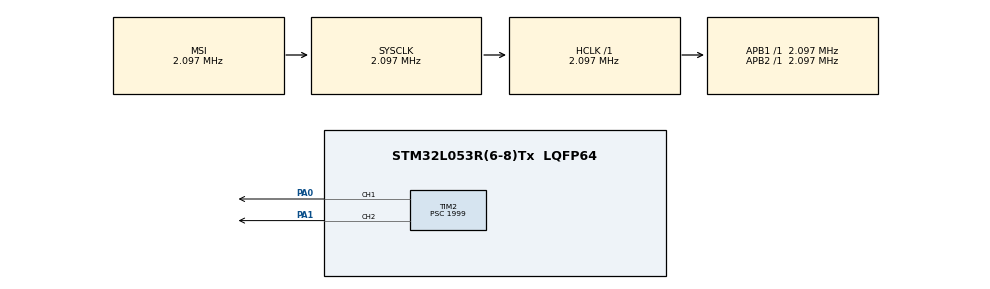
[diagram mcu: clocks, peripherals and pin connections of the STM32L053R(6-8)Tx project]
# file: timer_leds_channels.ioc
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Dma.Request0=TIM2_UP
Dma.TIM2_UP.0.Direction=DMA_PERIPH_TO_MEMORY
Dma.TIM2_UP.0.Instance=DMA1_Channel2
Dma.TIM2_UP.0.MemDataAlignment=DMA_MDATAALIGN_HALFWORD
Dma.TIM2_UP.0.MemInc=DMA_MINC_ENABLE
Dma.TIM2_UP.0.Mode=DMA_CIRCULAR
Dma.TIM2_UP.0.PeriphDataAlignment=DMA_PDATAALIGN_HALFWORD
Dma.TIM2_UP.0.PeriphInc=DMA_PINC_DISABLE
Dma.TIM2_UP.0.Priority=DMA_PRIORITY_LOW
Mcu.Family=STM32L0
Mcu.Name=STM32L053R(6-8)Tx
Mcu.Package=LQFP64
NVIC.DMA1_Channel2_3_IRQn=true\:0\:0\:false\:false\:true\:false\:true\:true
NVIC.TIM2_IRQn=true\:0\:0\:false\:false\:true\:true\:true\:true
PA0.Signal=S_TIM2_CH1
PA1.Signal=S_TIM2_CH2
ProjectManager.HeapSize=0x200
ProjectManager.StackSize=0x400
ProjectManager.TargetToolchain=STM32CubeIDE
RCC.AHBFreq_Value=2097000
RCC.APB1Freq_Value=2097000
RCC.APB1TimFreq_Value=2097000
RCC.APB2Freq_Value=2097000
RCC.APB2TimFreq_Value=2097000
RCC.HSE_VALUE=8000000
RCC.HSI16_VALUE=16000000
RCC.HSI48_VALUE=48000000
RCC.HSI_VALUE=16000000
RCC.LSE_VALUE=32768
RCC.MSI_VALUE=2097000
RCC.SYSCLKFreq_VALUE=2097000
RCC.VCOOutputFreq_Value=48000000
SH.S_TIM2_CH1.0=TIM2_CH1,Output Compare1 CH1
SH.S_TIM2_CH2.0=TIM2_CH2,Output Compare2 CH2
TIM2.Channel-Output\ Compare1\ CH1=TIM_CHANNEL_1
TIM2.Channel-Output\ Compare2\ CH2=TIM_CHANNEL_2
TIM2.OCMode_1=TIM_OCMODE_TOGGLE
TIM2.OCMode_2=TIM_OCMODE_TOGGLE
TIM2.Period=999
TIM2.Prescaler=1999
VP_TIM2_VS_ClockSourceINT.Mode=Internal
board=custom

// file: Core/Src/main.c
/* USER CODE BEGIN Header */
/**
  ******************************************************************************
  * @file           : main.c
  * @brief          : Main program body
  ******************************************************************************
  * @attention
  *
  * Copyright (c) 2023 STMicroelectronics.
  * All rights reserved.
  *
  * This software is licensed under terms that can be found in the LICENSE file
  * in the root directory of this software component.
  * If no LICENSE file comes with this software, it is provided AS-IS.
  *
  ******************************************************************************
  */
/* USER CODE END Header */
#include "main.h"

TIM_HandleTypeDef htim2;
DMA_HandleTypeDef hdma_tim2_up;

void SystemClock_Config(void);
static void MX_GPIO_Init(void);
static void MX_DMA_Init(void);
static void MX_TIM2_Init(void);

int main(void)
{

  /* MCU Configuration--------------------------------------------------------*/

  /* Reset of all peripherals, Initializes the Flash interface and the Systick. */
  HAL_Init();

  /* Configure the system clock */
  SystemClock_Config();

  /* Initialize all configured peripherals */
  MX_GPIO_Init();
  MX_DMA_Init();
  MX_TIM2_Init();
  /* USER CODE BEGIN 2 */
//  uint8_t data[] = {0xFF, 0x0};
//  HAL_TIM_Base_Start(&htim2);
//  HAL_DMA_Start(&hdma_tim2_up, (uint32_t)data, (uint32_t)&GPIOA->ODR, 2);
//  __HAL_TIM_ENABLE_DMA(&htim2, TIM_DMA_UPDATE);
  HAL_TIM_OC_Start(&htim2, TIM_CHANNEL_1);
  HAL_TIM_OC_Start(&htim2, TIM_CHANNEL_2);
  /* USER CODE END 2 */

  /* Infinite loop */
  while (1)
  {

  }
}

void SystemClock_Config(void)
{
  RCC_OscInitTypeDef RCC_OscInitStruct = {0};
  RCC_ClkInitTypeDef RCC_ClkInitStruct = {0};

  /** Configure the main internal regulator output voltage
  */
  __HAL_PWR_VOLTAGESCALING_CONFIG(PWR_REGULATOR_VOLTAGE_SCALE1);

  /** Initializes the RCC Oscillators according to the specified parameters
  * in the RCC_OscInitTypeDef structure.
  */
  RCC_OscInitStruct.OscillatorType = RCC_OSCILLATORTYPE_MSI;
  RCC_OscInitStruct.MSIState = RCC_MSI_ON;
  RCC_OscInitStruct.MSICalibrationValue = 0;
  RCC_OscInitStruct.MSIClockRange = RCC_MSIRANGE_5;
  RCC_OscInitStruct.PLL.PLLState = RCC_PLL_NONE;
  if (HAL_RCC_OscConfig(&RCC_OscInitStruct) != HAL_OK)
  {
    Error_Handler();
  }

  /** Initializes the CPU, AHB and APB buses clocks
  */
  RCC_ClkInitStruct.ClockType = RCC_CLOCKTYPE_HCLK|RCC_CLOCKTYPE_SYSCLK
                              |RCC_CLOCKTYPE_PCLK1|RCC_CLOCKTYPE_PCLK2;
  RCC_ClkInitStruct.SYSCLKSource = RCC_SYSCLKSOURCE_MSI;
  RCC_ClkInitStruct.AHBCLKDivider = RCC_SYSCLK_DIV1;
  RCC_ClkInitStruct.APB1CLKDivider = RCC_HCLK_DIV1;
  RCC_ClkInitStruct.APB2CLKDivider = RCC_HCLK_DIV1;

  if (HAL_RCC_ClockConfig(&RCC_ClkInitStruct, FLASH_LATENCY_0) != HAL_OK)
  {
    Error_Handler();
  }
}

static void MX_TIM2_Init(void)
{

  TIM_ClockConfigTypeDef sClockSourceConfig = {0};
  TIM_MasterConfigTypeDef sMasterConfig = {0};
  TIM_OC_InitTypeDef sConfigOC = {0};

  htim2.Instance = TIM2;
  htim2.Init.Prescaler = 1999;
  htim2.Init.CounterMode = TIM_COUNTERMODE_UP;
  htim2.Init.Period = 999;
  htim2.Init.ClockDivision = TIM_CLOCKDIVISION_DIV1;
  htim2.Init.AutoReloadPreload = TIM_AUTORELOAD_PRELOAD_DISABLE;
  if (HAL_TIM_Base_Init(&htim2) != HAL_OK)
  {
    Error_Handler();
  }
  sClockSourceConfig.ClockSource = TIM_CLOCKSOURCE_INTERNAL;
  if (HAL_TIM_ConfigClockSource(&htim2, &sClockSourceConfig) != HAL_OK)
  {
    Error_Handler();
  }
  if (HAL_TIM_OC_Init(&htim2) != HAL_OK)
  {
    Error_Handler();
  }
  sMasterConfig.MasterOutputTrigger = TIM_TRGO_RESET;
  sMasterConfig.MasterSlaveMode = TIM_MASTERSLAVEMODE_DISABLE;
  if (HAL_TIMEx_MasterConfigSynchronization(&htim2, &sMasterConfig) != HAL_OK)
  {
    Error_Handler();
  }
  sConfigOC.OCMode = TIM_OCMODE_TOGGLE;
  sConfigOC.Pulse = 0;
  sConfigOC.OCPolarity = TIM_OCPOLARITY_HIGH;
  sConfigOC.OCFastMode = TIM_OCFAST_DISABLE;
  if (HAL_TIM_OC_ConfigChannel(&htim2, &sConfigOC, TIM_CHANNEL_1) != HAL_OK)
  {
    Error_Handler();
  }
  if (HAL_TIM_OC_ConfigChannel(&htim2, &sConfigOC, TIM_CHANNEL_2) != HAL_OK)
  {
    Error_Handler();
  }
  HAL_TIM_MspPostInit(&htim2);

}

static void MX_DMA_Init(void)
{

  /* DMA controller clock enable */
  __HAL_RCC_DMA1_CLK_ENABLE();

  /* DMA interrupt init */
  /* DMA1_Channel2_3_IRQn interrupt configuration */
  HAL_NVIC_SetPriority(DMA1_Channel2_3_IRQn, 0, 0);
  HAL_NVIC_EnableIRQ(DMA1_Channel2_3_IRQn);

}

static void MX_GPIO_Init(void)
{
  GPIO_InitTypeDef GPIO_InitStruct = {0};

  /* GPIO Ports Clock Enable */
  __HAL_RCC_GPIOA_CLK_ENABLE();
  __HAL_RCC_GPIOB_CLK_ENABLE();

  /*Configure GPIO pin Output Level */
  HAL_GPIO_WritePin(GPIOA, GPIO_PIN_1|GPIO_PIN_4|GPIO_PIN_5, GPIO_PIN_RESET);

  /*Configure GPIO pins : PA1 PA4 PA5 */
  GPIO_InitStruct.Pin = GPIO_PIN_1|GPIO_PIN_4|GPIO_PIN_5;
  GPIO_InitStruct.Mode = GPIO_MODE_OUTPUT_PP;
  GPIO_InitStruct.Pull = GPIO_NOPULL;
  GPIO_InitStruct.Speed = GPIO_SPEED_FREQ_LOW;
  HAL_GPIO_Init(GPIOA, &GPIO_InitStruct);

}

void Error_Handler(void)
{
  __disable_irq();
  while (1)
  {
  }
}
